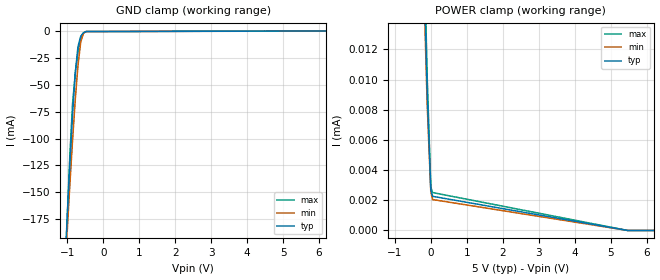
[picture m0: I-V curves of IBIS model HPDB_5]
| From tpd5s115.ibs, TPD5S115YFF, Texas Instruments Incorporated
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[Model]   HPDB_5
Model_type   Input
Vinl = 0.8V
Vinh = 2.000V
|   typ   min   max
|   (slow)   (nom)   (fast)
C_comp   5.3684pF   5.3681pF   5.4177pF
[Voltage Range]   5.000V   4.500V   5.500V
|Junction temperature
[Temperature Range]   40.0   100.0   -40.0
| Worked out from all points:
|   GND clamp passes 1 mA (typ) near -0.52 V on its own axis
|ambient temperature   25   85   -40|
[GND Clamp]
|   Voltage   I(typ)   I(min)   I(max)
-5V       -4.31A     -3.753A    -5.056A
-1.08V    -228mA     -234.2mA   -241.8mA
-1.005V   -173.9mA   -187.3mA   -175.4mA
-929.6mV  -123.3mA   -142.8mA   -115.1mA
-854.3mV  -77.2mA    -101.2mA   -67.44mA
-778.9mV  -38.7mA    -63.48mA   -38.81mA
-703.5mV  -14.29mA   -31.76mA   -19.36mA
-628.1mV  -4.804mA   -10.24mA   -7.097mA
-552.8mV  -1.431mA   -1.998mA   -1.764mA
-477.4mV  -368.2uA   -380.7uA   -360.4uA
10V       459.2uA    372.7uA    555.3uA
[POWER Clamp]
|   Voltage   I(typ)   I(min)   I(max)
-5V       456.9uA    414.4uA    506.9uA
-1.533V   140uA      127uA      155.4uA
-1.457V   133.2uA    120.8uA    147.7uA
-1.382V   126.3uA    114.5uA    140.1uA
-1.307V   119.4uA    108.3uA    132.5uA
-1.231V   112.5uA    102uA      124.8uA
-1.156V   105.6uA    95.79uA    117.2uA
-100.5mV  9.183uA    8.329uA    10.19uA
0V        2.709uA    2.549uA    2.897uA
50.25mV   2.262uA    2.048uA    2.512uA
5.477V    0A         0A         0A
10V       0A         0A         0A
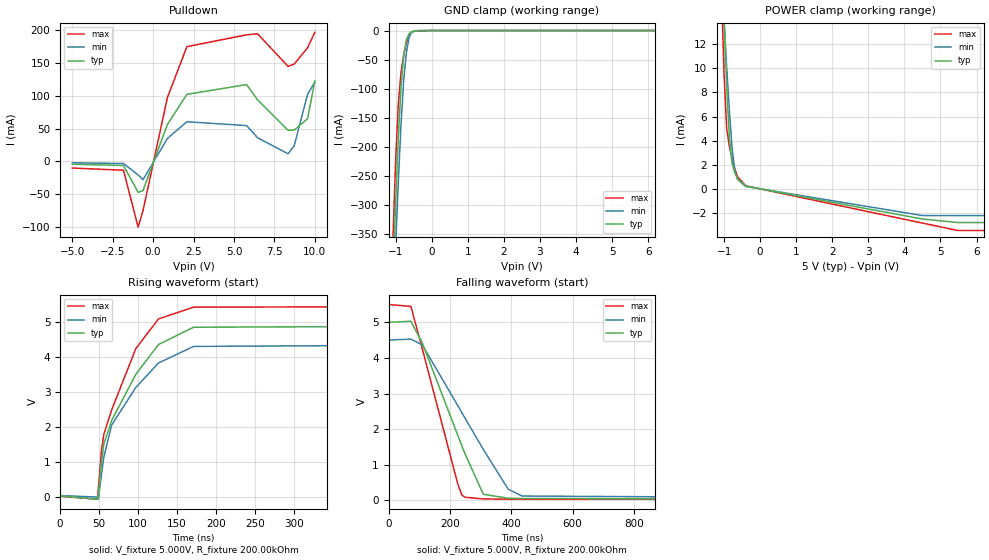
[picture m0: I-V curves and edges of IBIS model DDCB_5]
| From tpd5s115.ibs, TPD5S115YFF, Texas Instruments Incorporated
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[Model]   DDCB_5
Model_type   I/O_open_sink
Vinl = 1.5V
Vinh = 3.5V
Vmeas = 2.45V
Cref = 750pF
Vref = 0V
Rref = 200000
|   typ   min   max
|3-state
C_comp   7.0767pF   7.0022pF   7.3859pF
|pulldown
|C_comp   7.0535pF   7.0011pF   7.1479pF
[Voltage Range]   5.000V   4.500V   5.500V
|Junction temperature
[Temperature Range]   40.0   100.0   -40.0
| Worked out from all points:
|   slope of the pulldown table from 0 to 0.75 V, typ, clamps not added: 15.3 ohm
|   GND clamp passes 1 mA (typ) near -0.50 V on its own axis
|   POWER clamp passes 1 mA (typ) near -0.65 V on its own axis
|   falling waveform, V_fixture 5.000V, R_fixture 200.00kOhm: 20-80 % time 134ns typ, 180ns min, 99.3ns max; typ from 5 V to 0.038 V
|   rising waveform, V_fixture 5.000V, R_fixture 200.00kOhm: 20-80 % time 58.8ns typ, 60.5ns min, 48.8ns max; typ from 0.038 V to 5 V
|ambient temperature   25   85   -40|
[Pulldown]
|   Voltage   I(typ)   I(min)   I(max)
-5V       -4.205mA   -2.072mA   -10.01mA
-1.834V   -6.12mA    -3.042mA   -13.45mA
-929.6mV  -47.15mA   -20.58mA   -100.3mA
-628.1mV  -44.37mA   -27.94mA   -75.29mA
879.4mV   56.38mA    35.02mA    97.35mA
2.085V    102.5mA    60.66mA    175.3mA
5.779V    117.4mA    54.79mA    193.4mA
6.457V    94.06mA    36.25mA    195mA
8.342V    47.57mA    11.77mA    145.2mA
8.719V    47.92mA    23.89mA    148.6mA
9.548V    65.19mA    102.4mA    173.6mA
10V       123.1mA    121.4mA    197.2mA
[GND Clamp]
|   Voltage   I(typ)   I(min)   I(max)
-5V       -8.936A    -8.262A    -9.974A
-1.08V    -427.9mA   -493.7mA   -364.7mA
-1.005V   -301.3mA   -374.9mA   -228.2mA
-929.6mV  -186.9mA   -263.1mA   -127.9mA
-854.3mV  -97.29mA   -163.2mA   -72.61mA
-778.9mV  -43.47mA   -85.39mA   -42.02mA
-703.5mV  -15.76mA   -37.55mA   -21.18mA
-628.1mV  -5.483mA   -11.62mA   -7.992mA
-552.8mV  -1.804mA   -2.412mA   -2.202mA
-402mV    -290.9uA   -265.8uA   -303.3uA
0V        0A         0A         0A
10V       0A         0A         0A
[POWER Clamp]
|   Voltage   I(typ)   I(min)   I(max)
-5V       209mA      51.12mA    403.3mA
-1.08V    20.44mA    18.55mA    17.24mA
-1.005V   14.25mA    14.28mA    9.755mA
-929.6mV  8.607mA    10.2mA     5.047mA
-854.3mV  4.241mA    6.459mA    3.512mA
-778.9mV  2.132mA    3.398mA    2.539mA
-703.5mV  1.349mA    1.541mA    1.698mA
-628.1mV  849.4uA    783.3uA    1.016mA
-402mV    232.5uA    209.5uA    257.5uA
4.497V    -2.494mA   -2.206mA   -2.83mA
5.477V    -2.786mA   -2.206mA   -3.446mA
10V       -2.786mA   -2.206mA   -3.446mA
[Ramp]
R_load = 200.00kOhm
|   typ   min   max
dV/dt_r   2.977V/58.839ns   2.671V/60.543ns   3.284V/48.764ns
dV/dt_f   2.977V/133.585ns   2.671V/180.382ns   3.284V/99.289ns
[Falling Waveform]
V_fixture = 5.000V
V_fixture_min = 4.500V
V_fixture_max = 5.500V
R_fixture = 200.00kOhm
|   Time   V(typ)   V(min)   V(max)
0s        5V         4.5V       5.5V
73ns      5.029V     4.528V     5.446V
110ns     4.423V     4.366V     4.258V
226ns     1.821V     2.658V     453.1mV
239ns     1.534V     2.463V     149mV
250ns     1.294V     2.299V     83.92mV
309ns     169.4mV    1.43V      39.54mV
390ns     58.28mV    312.4mV    31.79mV
435ns     50.09mV    120.9mV    30.28mV
1.913us   38.1mV     47.91mV    27.48mV
[Rising Waveform]
V_fixture = 5.000V
V_fixture_min = 4.500V
V_fixture_max = 5.500V
R_fixture = 200.00kOhm
|   Time   V(typ)   V(min)   V(max)
0s        38.1mV     47.91mV    27.48mV
48ns      -61.08mV   2.961mV    -56.84mV
49ns      65.77mV    -50.28mV   262.2mV
53ns      994.9mV    661.8mV    1.34V
56ns      1.518V     1.144V     1.796V
66ns      2.19V      2.058V     2.49V
97ns      3.507V     3.132V     4.243V
126ns     4.358V     3.829V     5.086V
171ns     4.851V     4.304V     5.424V
1.913us   5V         4.5V       5.5V
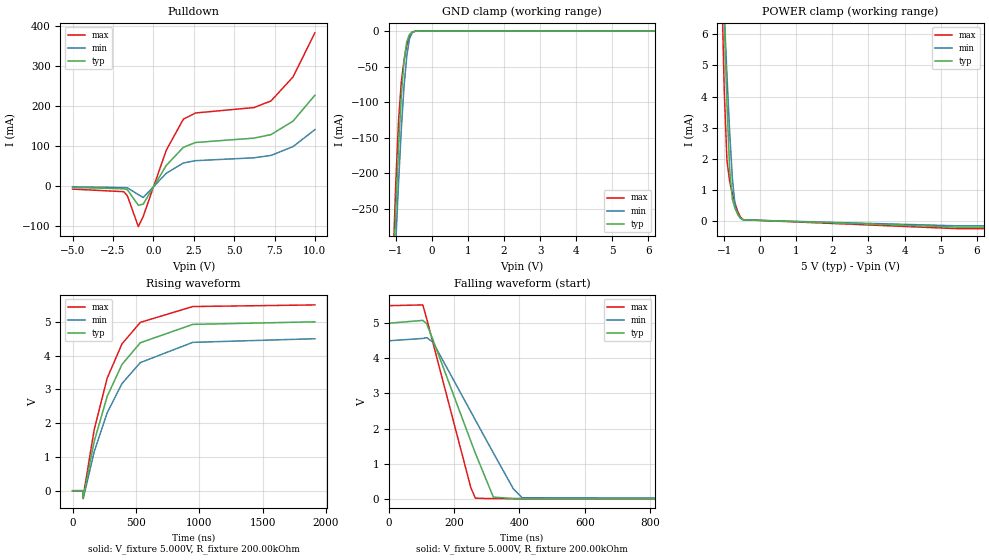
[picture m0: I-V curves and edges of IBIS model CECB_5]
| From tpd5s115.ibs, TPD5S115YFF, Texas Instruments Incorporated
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[Model]   CECB_5
Model_type   I/O_open_sink
Vinl = 0.99V
Vinh = 2.31V
Vmeas = 1.500V
Cref = 750pF
Vref = 0V
Rref = 200000
|   typ   min   max
|3-state   (nom)   (slow)   (fast)
C_comp   6.3194pF   6.1953pF   6.5799pF
|pulldown   (slow)   (nom)   (fast)
|C_comp   6.2493pF   6.2187pF   6.3143pF
[Voltage Range]   5.000V   4.500V   5.500V
|Junction temperature
[Temperature Range]   40.0   100.0   -40.0
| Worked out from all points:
|   slope of the pulldown table from 0 to 0.75 V, typ, clamps not added: 15.3 ohm
|   GND clamp passes 1 mA (typ) near -0.52 V on its own axis
|   POWER clamp passes 1 mA (typ) near -0.80 V on its own axis
|   falling waveform, V_fixture 5.000V, R_fixture 200.00kOhm: 20-80 % time 121ns typ, 158ns min, 92.3ns max; typ from 5 V to 0.003 V
|   rising waveform, V_fixture 5.000V, R_fixture 200.00kOhm: 20-80 % time 294ns typ, 327ns min, 263ns max; typ from 0.003 V to 5 V
|ambient temperature   25   85   -40|
[Pulldown]
|   Voltage   I(typ)   I(min)   I(max)
-5V       -2.836mA   -1.368mA   -6.94mA
-1.834V   -6.121mA   -3.042mA   -13.38mA
-1.608V   -8.356mA   -3.815mA   -23.45mA
-929.6mV  -47.15mA   -20.58mA   -100.3mA
-628.1mV  -44.37mA   -27.94mA   -75.29mA
804mV     52.23mA    32.51mA    90.22mA
1.859V    97.07mA    58.09mA    167.2mA
2.613V    109.1mA    63.86mA    182.6mA
6.231V    120mA      71mA       196.1mA
7.286V    128.8mA    76.87mA    212.6mA
8.643V    162.2mA    98.76mA    272.1mA
10V       226.7mA    141.1mA    382.2mA
[GND Clamp]
|   Voltage   I(typ)   I(min)   I(max)
-5V       -6.932A    -6.231A    -8.002A
-1.08V    -346.4mA   -381.6mA   -320.4mA
-1.005V   -251mA     -295.2mA   -211.5mA
-929.6mV  -163.7mA   -213.5mA   -125.7mA
-854.3mV  -91.68mA   -139.3mA   -71.92mA
-778.9mV  -42.54mA   -78.51mA   -41.46mA
-703.5mV  -15.31mA   -36.26mA   -20.71mA
-628.1mV  -5.132mA   -11.2mA    -7.595mA
-552.8mV  -1.51mA    -2.136mA   -1.869mA
-477.4mV  -369.1uA   -385.8uA   -358.6uA
-326.6mV  -22.71uA   -22.98uA   -19.28uA
10V       0A         0A         0A
[POWER Clamp]
|   Voltage   I(typ)   I(min)   I(max)
-5V       104.9mA    27.74mA    200.2mA
-1.08V    9.578mA    8.791mA    7.884mA
-1.005V   6.549mA    6.701mA    4.221mA
-929.6mV  3.792mA    4.702mA    1.95mA
-854.3mV  1.673mA    2.869mA    1.279mA
-778.9mV  705.6uA    1.375mA    889.3uA
-703.5mV  399.6uA    507.9uA    560.9uA
-628.1mV  221uA      204.8uA    300uA
-552.8mV  102.6uA    90.38uA    125.8uA
-477.4mV  41.84uA    38.78uA    44.14uA
5.477V    -193.4uA   -151.9uA   -242.6uA
10V       -193.4uA   -151.9uA   -242.6uA
[Ramp]
R_load = 200.00kOhm
|   typ   min   max
dV/dt_r   2.998V/294.388ns   2.698V/326.974ns   3.299V/263.202ns
dV/dt_f   2.998V/120.784ns   2.698V/158.096ns   3.299V/92.261ns
[Falling Waveform]
V_fixture = 5.000V
V_fixture_min = 4.500V
V_fixture_max = 5.500V
R_fixture = 200.00kOhm
|   Time   V(typ)   V(min)   V(max)
0s        5V         4.5V       5.5V
104ns     5.08V      4.566V     5.521V
116ns     4.984V     4.59V      5.126V
135ns     4.53V      4.46V      4.443V
251ns     1.64V      2.481V     318.6mV
265ns     1.296V     2.241V     15.95mV
320ns     47.1mV     1.306V     3.729mV
381ns     6.081mV    287.3mV    2.827mV
408ns     5.005mV    28.8mV     2.674mV
1.913us   3.07mV     3.9mV      2.222mV
[Rising Waveform]
V_fixture = 5.000V
V_fixture_min = 4.500V
V_fixture_max = 5.500V
R_fixture = 200.00kOhm
|   Time   V(typ)   V(min)   V(max)
0s        3.07mV     3.9mV      2.222mV
81ns      3.044mV    3.903mV    2.374mV
82ns      -122.1mV   -45.66mV   -214.2mV
84ns      -202.9mV   -233.4mV   -157.6mV
171ns     1.463V     1.158V     1.811V
273ns     2.792V     2.307V     3.33V
390ns     3.738V     3.172V     4.347V
535ns     4.381V     3.794V     4.984V
949ns     4.924V     4.392V     5.452V
1.913us   5V         4.5V       5.5V
